VERSION 5.8 ;
BUSBITCHARS "[]" ;
DIVIDERCHAR "/" ;
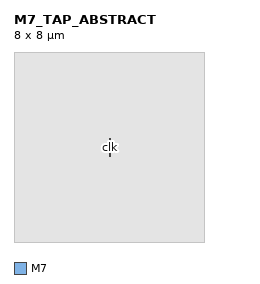
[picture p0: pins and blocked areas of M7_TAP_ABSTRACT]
MACRO M7_TAP_ABSTRACT
 CLASS BLOCK ;
 ORIGIN 0 0 ;
 SIZE 8 BY 8 ;
 SYMMETRY X Y ;
 PIN clk
  DIRECTION INPUT ;
  USE CLOCK ;
  PORT
   LAYER M7 ;
   RECT 4.032 3.608 4.064 4.376 ;
  END
 END clk
 OBS
  LAYER M1 ; RECT 0 0 8 8 ;
  LAYER M2 ; RECT 0 0 8 8 ;
  LAYER M3 ; RECT 0 0 8 8 ;
  LAYER M4 ; RECT 0 0 8 8 ;
  LAYER M5 ; RECT 0 0 8 8 ;
  LAYER M6 ; RECT 0 0 8 8 ;
  LAYER M7 ; RECT 0 0 8 8 ;
 END
END M7_TAP_ABSTRACT
END LIBRARY
